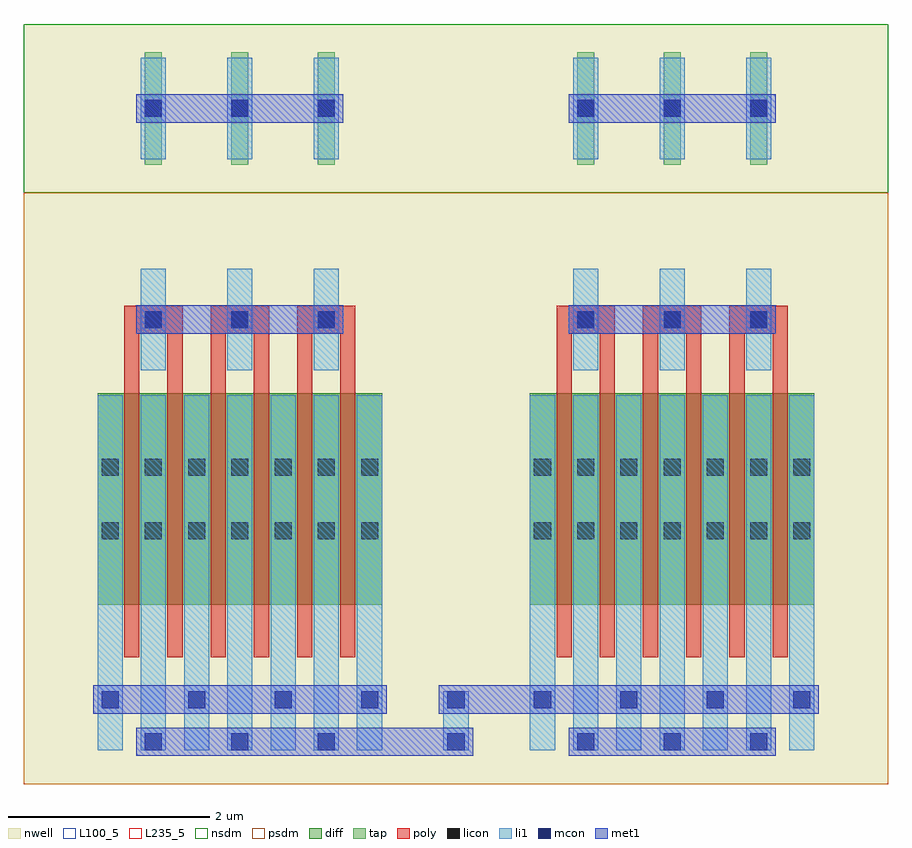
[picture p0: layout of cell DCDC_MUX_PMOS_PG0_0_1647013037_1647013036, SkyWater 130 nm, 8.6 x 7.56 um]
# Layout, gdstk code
from math import pi, radians
import gdstk
lib = gdstk.Library(unit=1e-6, precision=1e-09)
def R(c, l, rs):  # rectangles x0, y0, x1, y1
    for r in rs: c.add(gdstk.rectangle(r[:2], r[2:], *l))
def A(c, l, x, y, w, h, nx, ny, dx, dy):  # array of equal rectangles
    R(c, l, [(x+i*dx, y+j*dy, x+i*dx+w, y+j*dy+h) for i in range(nx) for j in range(ny)])
def P(c, l, *ps):  # polygons
    for p in ps: c.add(gdstk.Polygon(p, *l))
nwell = (64, 20)
diff = (65, 20)
tap = (65, 44)
poly = (66, 20)
licon = (66, 44)
li1 = (67, 20)
mcon = (67, 44)
met1 = (68, 20)
nsdm = (93, 44)
psdm = (94, 20)
L100_5 = (100, 5)
L235_5 = (235, 5)

pmos_4t_84335382_x3_y1_1 = lib.new_cell('PMOS_4T_84335382_X3_Y1_1647013035_1647013037_1647013036')
R(pmos_4t_84335382_x3_y1_1, nwell, [(0,0,4.3,7.56)])
R(pmos_4t_84335382_x3_y1_1, diff, [(0.735,1.785,3.565,3.885)])
A(pmos_4t_84335382_x3_y1_1, tap, 1.205, 6.16, 0.17, 1.12, 3, 1, 0.86, 0)
A(pmos_4t_84335382_x3_y1_1, poly, 1, 1.26, 0.15, 3.36, 6, 1, 0.43, 0)
A(pmos_4t_84335382_x3_y1_1, poly, 1, 4.485, 0.58, 0.27, 3, 1, 0.86, 0)
A(pmos_4t_84335382_x3_y1_1, licon, 0.775, 2.435, 0.17, 0.17, 3, 2, 0.43, 0.63)
A(pmos_4t_84335382_x3_y1_1, licon, 1.635, 2.435, 0.17, 0.17, 3, 2, 0.43, 0.63)
A(pmos_4t_84335382_x3_y1_1, licon, 2.495, 2.435, 0.17, 0.17, 3, 2, 0.43, 0.63)
A(pmos_4t_84335382_x3_y1_1, licon, 1.205, 4.535, 0.17, 0.17, 3, 2, 0.86, 2.1)
A(pmos_4t_84335382_x3_y1_1, li1, 0.735, 0.335, 0.25, 3.53, 7, 1, 0.43, 0)
A(pmos_4t_84335382_x3_y1_1, li1, 1.165, 4.115, 0.25, 1.01, 3, 2, 0.86, 2.1)
A(pmos_4t_84335382_x3_y1_1, mcon, 1.205, 0.335, 0.17, 0.17, 3, 2, 0.86, 4.2)
A(pmos_4t_84335382_x3_y1_1, mcon, 0.775, 0.755, 0.17, 0.17, 4, 1, 0.86, 0)
A(pmos_4t_84335382_x3_y1_1, mcon, 1.205, 6.635, 0.17, 0.17, 3, 1, 0.86, 0)
R(pmos_4t_84335382_x3_y1_1, met1, [(1.12,0.28,3.18,0.56), (0.69,0.7,3.61,0.98), (1.12,4.48,3.18,4.76), (1.12,6.58,3.18,6.86)])
R(pmos_4t_84335382_x3_y1_1, nsdm, [(0,5.88,4.3,7.56)])
R(pmos_4t_84335382_x3_y1_1, psdm, [(0,0,4.3,5.88)])
R(pmos_4t_84335382_x3_y1_1, L100_5, [(0,0,4.3,7.56)])

dcdc_mux_pmos_pg0_0_1647 = lib.new_cell('DCDC_MUX_PMOS_PG0_0_1647013037_1647013036')
R(dcdc_mux_pmos_pg0_0_1647, li1, [(4.175,0.335,4.425,0.505), (4.175,0.335,4.425,0.505), (4.175,0.42,4.425,0.84), (4.175,0.755,4.425,0.925), (4.175,0.755,4.425,0.925)])
R(dcdc_mux_pmos_pg0_0_1647, mcon, [(4.215,0.335,4.385,0.505), (4.215,0.335,4.385,0.505), (4.215,0.755,4.385,0.925), (4.215,0.755,4.385,0.925)])
R(dcdc_mux_pmos_pg0_0_1647, met1, [(3.01,0.28,4.3,0.56), (4.13,0.28,4.47,0.56), (4.13,0.28,4.47,0.56), (4.13,0.7,4.47,0.98), (4.13,0.7,4.47,0.98), (4.3,0.7,5.16,0.98)])
P(dcdc_mux_pmos_pg0_0_1647, met1, [(0,0),(0,0),(0,0),(0,0)],
  [(0,0),(0,0),(0,0),(0,0)],
  [(0,0),(0,0),(0,0),(0,0)],
  [(0,0),(0,0),(0,0),(0,0)],
  [(0,0),(0,0),(0,0),(0,0)],
  [(0,0),(0,0),(0,0),(0,0)],
  [(0,0),(0,0),(0,0),(0,0)],
  [(0,0),(0,0),(0,0),(0,0)])
R(dcdc_mux_pmos_pg0_0_1647, L235_5, [(0,0,8.6,7.56)])
dcdc_mux_pmos_pg0_0_1647.add(gdstk.Reference(pmos_4t_84335382_x3_y1_1, (4.3,0)))
dcdc_mux_pmos_pg0_0_1647.add(gdstk.Reference(pmos_4t_84335382_x3_y1_1, (4.3,0), rotation=pi, x_reflection=True))

lib.write_gds('DCDC_MUX_PMOS_PG0_0_1647013037_1647013036.gds')
